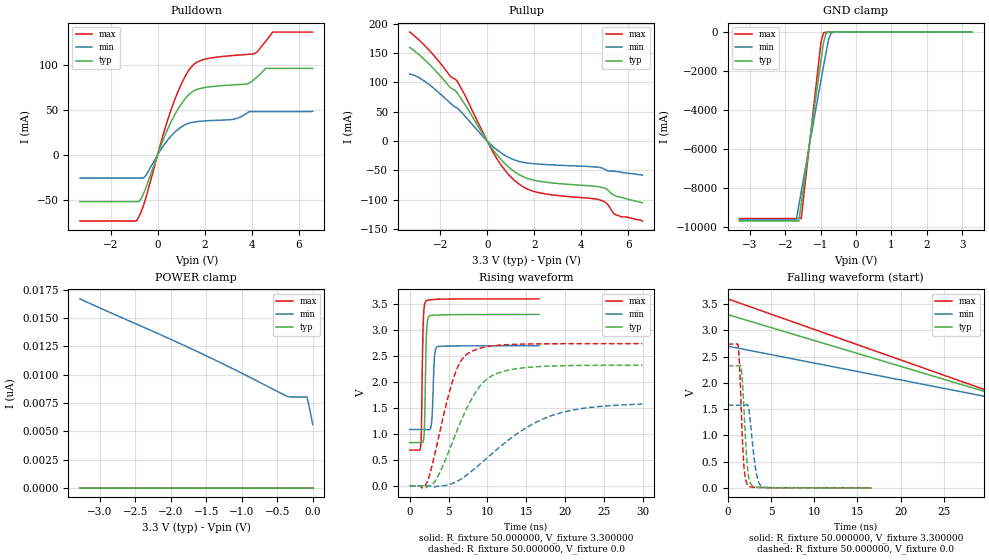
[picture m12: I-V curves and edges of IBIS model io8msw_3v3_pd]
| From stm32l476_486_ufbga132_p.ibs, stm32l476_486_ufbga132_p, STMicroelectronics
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|   Model io8msw_3v3_pd
[Model]  io8msw_3v3_pd
Model_type I/O
Polarity   Non-Inverting
Enable   Active-Low
Vinl =   0.990000V
Vinh =   2.310000V
Vmeas =  1.650000V
Cref =   100.000000nF
Rref =   1.000000k
Vref =   3.300000V
C_comp   2.968600pF   2.938100pF   3.196200pF
[Temperature Range]   25.000000   0.125000k   -40.000000
[Pullup Reference]   3.300000V   2.700000V   3.600000V
[Pulldown Reference]   0.0V   0.0V   0.0V
[POWER Clamp Reference]   3.300000V   2.700000V   3.600000V
[GND Clamp Reference]   0.0V   0.0V   0.0V
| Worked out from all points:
|   slope of the pulldown table from 0 to 0.495 V, typ, clamps not added: 15.4 ohm
|   slope of the pullup table from 0 to 0.495 V, typ, clamps not added: 18.1 ohm
|   GND clamp passes 1 mA (typ) near -0.58 V on its own axis
|   rising waveform, R_fixture 50.000000, V_fixture 3.300000: 20-80 % time 196ps typ, 238ps min, 193ps max; typ from 0.835 V to 3.3 V
|   rising waveform, R_fixture 50.000000, V_fixture 0.0: 20-80 % time 4.25ns typ, 8.5ns min, 2.78ns max; typ from 0 V to 2.32 V
|   falling waveform, R_fixture 50.000000, V_fixture 3.300000: 20-80 % time 30ns typ, 30.1ns min, 30ns max; typ from 3.3 V to 0.835 V
|   falling waveform, R_fixture 50.000000, V_fixture 0.0: 20-80 % time 485ps typ, 657ps min, 409ps max; typ from 2.32 V to 0 V
[Pulldown]
|Voltage   I(typ)   I(min)   I(max)
-3.3V     -51.63mA   -25.53mA   -73.04mA
-900mV    -51.63mA   -25.53mA   -73.04mA
-500mV    -36.51mA   -22.79mA   -47.71mA
200mV     14.02mA    8.316mA    18.9mA
700mV     42.99mA    24.4mA     58.9mA
1.2V      63.06mA    33.8mA     88.14mA
1.6V      71.63mA    36.67mA    101.4mA
3.2V      77.51mA    39.29mA    110mA
4.1V      83.27mA    47.97mA    111.9mA
4.6V      95.8mA     47.97mA    125.7mA
4.9V      95.8mA     47.97mA    136mA
6.6V      95.8mA     48.43mA    136mA
[Pullup]
|Voltage   I(typ)   I(min)   I(max)
-3.3V     159.6mA    114.2mA    185.6mA
-2.6V     136.1mA    100mA      160.2mA
-1.6V     92.48mA    65.73mA    111.9mA
-1.3V     83.31mA    56.77mA    103.4mA
300mV     -17.49mA   -11.19mA   -22.71mA
800mV     -40.27mA   -25.28mA   -51.87mA
1.3V      -55.74mA   -33.93mA   -71.59mA
2.2V      -68.23mA   -39.11mA   -87.81mA
4.8V      -78.1mA    -45mA      -100.2mA
5.1V      -82mA      -50mA      -106.7mA
5.5V      -94mA      -52mA      -126mA
6.6V      -105mA     -58mA      -136mA
[GND_clamp]
|Voltage   I(typ)   I(min)   I(max)
-3.3V     -9.687A    -9.633A    -9.557A
-1.69V    -9.687A    -9.633A    -9.557A
-1.62V    -9.687A    -8.894A    -9.557A
-1.55V    -8.764A    -8.167A    -9.557A
-1.13V    -3.236A    -3.867A    -2.713A
-990mV    -1.417A    -2.448A    -480.2mA
-920mV    -530mA     -1.746A    -39.97mA
-850mV    -62.37mA   -1.055A    -14.05mA
-780mV    -12.06mA   -390.4mA   -9.024mA
-710mV    -4.91mA    -69.1mA    -5.331mA
-640mV    -2.318mA   -14.6mA    -2.508mA
3.28V     87.11uA    88.99uA    71.58uA
[POWER_clamp]
|Voltage   I(typ)   I(min)   I(max)
-3.28V    0A         16.68nA    0A
-1.64V    0A         12.07nA    0A
-1.08V    0A         10.37nA    0A
-360mV    0A         8.078nA    0A
-320mV    0A         8.02nA     0A
-80mV     0A         8.02nA     0A
-40mV     0A         6.883nA    0A
0V        0A         5.582nA    0A
[Ramp]
| variable   typ   min   max
dV/dt_r  1.37784/4.15448n   0.74394/6.12842n   1.64070/2.77201n
dV/dt_f  1.45425/3.56647n   0.79578/5.43603n   1.74045/2.48332n
R_load = 50.000000
[Rising Waveform]
R_fixture= 50.000000
V_fixture= 3.300000
V_fixture_min= 2.700000
V_fixture_max= 3.600000
|time   V(typ)   V(min)   V(max)
0s        834.7mV    1.086V     689.8mV
1.435ns   834.1mV    1.086V     788.2mV
1.735ns   856.4mV    1.086V     3.093V
1.902ns   1.143V     1.086V     3.479V
2.069ns   2.426V     1.086V     3.555V
2.269ns   3.157V     1.085V     3.574V
2.803ns   3.282V     1.206V     3.583V
3.17ns    3.286V     2.441V     3.588V
3.504ns   3.287V     2.672V     3.592V
16.62ns   3.299V     2.699V     3.599V
[Rising Waveform]
R_fixture= 50.000000
V_fixture= 0.0
V_fixture_min= 0.0
V_fixture_max= 0.0
|time   V(typ)   V(min)   V(max)
0s        3.854nV    95.34nV    3.47nV
2.222ns   -19.97mV   184.1uV    67.15mV
3.544ns   159.7mV    -6.951mV   818.9mV
5.526ns   854mV      50.68mV    2.024V
6.547ns   1.232V     129mV      2.396V
7.748ns   1.613V     258.3mV    2.574V
9.429ns   1.989V     470.8mV    2.665V
10.99ns   2.15V      673.9mV    2.7V
18.02ns   2.306V     1.342V     2.735V
29.91ns   2.323V     1.574V     2.738V
[Falling Waveform]
R_fixture= 50.000000
V_fixture= 3.300000
V_fixture_min= 2.700000
V_fixture_max= 3.600000
|time   V(typ)   V(min)   V(max)
0s        3.299V     2.699V     3.599V
50.05ns   834.8mV    1.089V     689.8mV
100.1ns   834.7mV    1.086V     689.8mV
4.955us   834.7mV    1.086V     689.8mV
[Falling Waveform]
R_fixture= 50.000000
V_fixture= 0.0
V_fixture_min= 0.0
V_fixture_max= 0.0
|time   V(typ)   V(min)   V(max)
0s        2.323V     1.574V     2.738V
1.168ns   2.323V     1.574V     2.725V
1.368ns   2.329V     1.574V     2.339V
1.535ns   2.296V     1.574V     1.62V
1.902ns   1.413V     1.573V     355.6mV
2.169ns   634.1mV    1.583V     103.6mV
2.402ns   232.3mV    1.531V     40.4mV
3.237ns   16.72mV    349.2mV    9.005mV
3.871ns   7.99mV     32.6mV     4.483mV
16.62ns   3.854nV    95.34nV    3.47nV
